VERSION 5.8 ;
BUSBITCHARS "[]" ;
DIVIDERCHAR "/" ;
UNITS
  DATABASE MICRONS 1000 ;
END UNITS
MANUFACTURINGGRID 0.005 ;
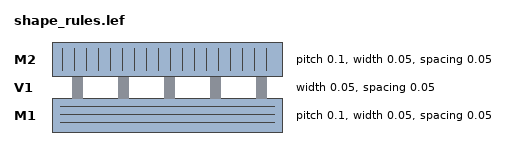
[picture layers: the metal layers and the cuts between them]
LAYER M1
  TYPE ROUTING ;
  DIRECTION HORIZONTAL ;
  PITCH 0.1 ;
  OFFSET 0.05 ;
  WIDTH 0.05 ;
  SPACING 0.05 ;
  PROPERTY LEF58_FORBIDDENSPACING "FORBIDDENSPACING 0.2 0.3 WIDTH 0.1 PRL 0.15 TWOEDGES 0.25 ;" ;
END M1
LAYER V1
  TYPE CUT ;
  SPACING 0.05 ;
  WIDTH 0.05 ;
END V1
LAYER M2
  TYPE ROUTING ;
  DIRECTION VERTICAL ;
  PITCH 0.1 ;
  OFFSET 0.05 ;
  WIDTH 0.05 ;
  SPACING 0.05 ;
  PROPERTY LEF58_EOLEXTENSIONSPACING "EOLEXTENSIONSPACING 0.08 ENDOFLINE 0.06 EXTENSION 0.03 ;" ;
END M2
END LIBRARY
